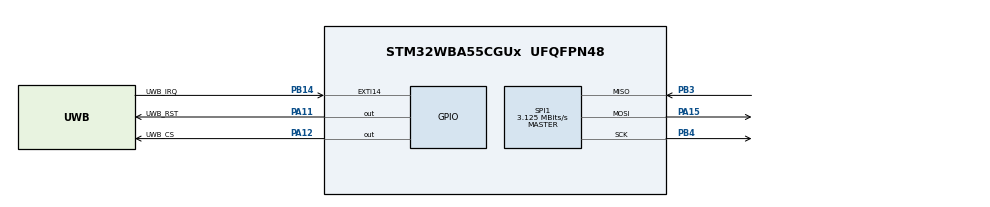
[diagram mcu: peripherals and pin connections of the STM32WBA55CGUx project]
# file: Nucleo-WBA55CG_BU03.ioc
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CORTEX_M33_NS.userName=CORTEX_M33
Mcu.Family=STM32WBA
Mcu.Name=STM32WBA55CGUx
Mcu.Package=UFQFPN48
NUCLEO-WBA55CG.BUTTON=1
NUCLEO-WBA55CG.BUTTON2=1
NUCLEO-WBA55CG.BUTTON3=1
NUCLEO-WBA55CG.LD1=true
NUCLEO-WBA55CG.LD2=true
NUCLEO-WBA55CG.LD3=true
NUCLEO-WBA55CG.VCP=true
NVIC.EXTI13_IRQn=true\:0\:0\:false\:false\:true\:false\:true\:true
NVIC.EXTI14_IRQn=true\:0\:0\:false\:false\:true\:true\:true\:true
NVIC.EXTI6_IRQn=true\:0\:0\:false\:false\:true\:false\:true\:true
NVIC.EXTI7_IRQn=true\:0\:0\:false\:false\:true\:false\:true\:true
NVIC.PriorityGroup=NVIC_PRIORITYGROUP_4
OSC_IN.GPIO_Label=RCC_OSC_IN
OSC_IN.Mode=HSE-External-Oscillator
OSC_IN.Signal=RCC_OSC_IN
OSC_OUT.GPIO_Label=RCC_OSC_OUT
OSC_OUT.Mode=HSE-External-Oscillator
OSC_OUT.Signal=RCC_OSC_OUT
PA11.GPIO_Label=UWB_RST
PA11.PinState=GPIO_PIN_SET
PA11.Signal=GPIO_Output
PA12.GPIO_Label=UWB_CS
PA12.PinState=GPIO_PIN_SET
PA12.Signal=GPIO_Output
PA13\ (JTMS/SWDIO).GPIO_Label=DEBUG_JTMS-SWDIO
PA13\ (JTMS/SWDIO).Mode=Serial_Wire
PA13\ (JTMS/SWDIO).Signal=DEBUG_JTMS-SWDIO
PA14\ (JTCK/SWCLK).GPIO_Label=DEBUG_JTCK-SWCLK
PA14\ (JTCK/SWCLK).Mode=Serial_Wire
PA14\ (JTCK/SWCLK).Signal=DEBUG_JTCK-SWCLK
PA15\ (JTDI).Mode=Full_Duplex_Master
PA15\ (JTDI).Signal=SPI1_MOSI
PA8.Signal=USART1_RX
PB12.Signal=USART1_TX
PB14.GPIO_Label=UWB_IRQ
PB14.Signal=GPXTI14
PB3\ (JTDO/TRACESWO).Mode=Full_Duplex_Master
PB3\ (JTDO/TRACESWO).Signal=SPI1_MISO
PB4\ (NJTRST).Mode=Full_Duplex_Master
PB4\ (NJTRST).Signal=SPI1_SCK
PC14-OSC32_IN.GPIO_Label=RCC_OSC32_IN
PC14-OSC32_IN.Signal=RCC_OSC32_IN
PC15-OSC32_OUT.GPIO_Label=RCC_OSC32_OUT
PC15-OSC32_OUT.Signal=RCC_OSC32_OUT
ProjectManager.HeapSize=0x200
ProjectManager.StackSize=0x400
ProjectManager.TargetToolchain=STM32CubeIDE
RCC.ADCFreq_Value=100000000
RCC.AHB5CLKDivider=DIV4
RCC.AHBFreq_Value=100000000
RCC.APB1Freq_Value=100000000
RCC.APB1TimFreq_Value=100000000
RCC.APB2Freq_Value=100000000
RCC.APB2TimFreq_Value=100000000
RCC.CortexFreq_Value=12500000
RCC.HCLKFreq_Value=100000000
RCC.HSE_VALUE=32000000
RCC.HSI_VALUE=16000000
RCC.LSE_VALUE=32768
RCC.LSI1_VALUE=32000
RCC.LSI2_VALUE=32000
RCC.PLLFRACN=4096
RCC.PLLN=12
RCC.PWR_Regulator_Voltage_Scale=PWR_REGULATOR_VOLTAGE_SCALE1
RCC.RTCClockSelection=RCC_RTCCLKSOURCE_LSE
RCC.SYSCLKFreq_VALUE=100000000
RCC.SYSCLKSourceVirtual=RCC_SYSCLKSOURCE_PLLCLK
RCC.VCOOutputFreq_Value=200000000
SPI1.BaudRatePrescaler=SPI_BAUDRATEPRESCALER_32
SPI1.CalculateBaudRate=3.125 MBits/s
SPI1.DataSize=SPI_DATASIZE_8BIT
SPI1.Direction=SPI_DIRECTION_2LINES
SPI1.Mode=SPI_MODE_MASTER
SPI1.VirtualType=VM_MASTER
VP_CORTEX_M33_NS_VS_Hclk.Mode=Hclk_Mode
VP_MEMORYMAP_VS_MEMORYMAP.Mode=CurAppReg
VP_NUCLEO-WBA55CG_VS_BSP_COMMON.Mode=COMMON
VP_PWR_VS_SECSignals.Mode=Security/Privilege
board=NUCLEO-WBA55CG

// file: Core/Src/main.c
/* USER CODE BEGIN Header */
/**
  ******************************************************************************
  * @file           : main.c
  * @brief          : Main program body
  ******************************************************************************
  * @attention
  *
  * Copyright (c) 2026 STMicroelectronics.
  * All rights reserved.
  *
  * This software is licensed under terms that can be found in the LICENSE file
  * in the root directory of this software component.
  * If no LICENSE file comes with this software, it is provided AS-IS.
  *
  ******************************************************************************
  */
/* USER CODE END Header */
#include "main.h"
#include "spi.h"
#include "gpio.h"

COM_InitTypeDef BspCOMInit;

void SystemClock_Config(void);

/* USER CODE BEGIN 0 */
#include <stdio.h>
#include <string.h>
#include "port.h"
#include "deca_device_api.h"
#include "dw3000_deca_regs.h"

#define TX_ANT_DLY 16385
#define RX_ANT_DLY 16385
#define ALL_MSG_SN_IDX 2
#define ALL_MSG_COMMON_LEN 10
#define RESP_MSG_POLL_RX_TS_IDX 10
#define RESP_MSG_RESP_TX_TS_IDX 14
#define POLL_RX_TO_RESP_TX_DLY_UUS 900 // Tag responds 900us after poll
#define UUS_TO_DWT_TIME 65536 // 1 uus = 65536 DWT time units

static dwt_config_t config = {
    5,               /* Channel number. */
    DWT_PLEN_128,    /* Preamble length. Used in TX only. */
    DWT_PAC8,        /* Preamble acquisition chunk size. Used in RX only. */
    9,               /* TX preamble code. Used in TX only. */
    9,               /* RX preamble code. Used in RX only. */
    1,               /* 0 to use standard 8 symbol SFD, 1 to use non-standard 8 symbol, 2 for non-standard 16 symbol SFD and 3 for 4z 8 symbol SDF type */
    DWT_BR_6M8,      /* Data rate. */
    DWT_PHRMODE_STD, /* PHY header mode. */
    DWT_PHRRATE_STD, /* PHY header rate. */
    (129 + 8 - 8),   /* SFD timeout (preamble length + 1 + SFD length - PAC size). Used in RX only. */
    DWT_STS_MODE_OFF,
    DWT_STS_LEN_64,  /* STS length, see allowed values in Enum dwt_sts_lengths_e */
    DWT_PDOA_M0      /* PDOA mode off */
};
static dwt_txconfig_t txconfig_options = {
    0x34,           /* PG delay. */
    0xfdfdfdfd,      /* TX power. */
    0x0             /* PG count. */
};

static uint8_t rx_buffer[20];
static uint8_t tx_resp_msg[] = {0x41, 0x88, 0, 0xCA, 0xDE, 'V', 'E', 'W', '0', 0xE1, 0, 0, 0, 0, 0, 0, 0, 0, 0, 0};
static uint8_t frame_seq_nb = 0;
static uint64_t poll_rx_ts;
static uint64_t resp_tx_ts;

static uint64_t get_rx_timestamp_u64(void)
{
    uint8_t ts_tab[5];
    uint64_t ts = 0;
    int i;
    dwt_readrxtimestamp(ts_tab, 0);
    for (i = 4; i >= 0; i--) {
        ts <<= 8;
        ts |= ts_tab[i];
    }
    return ts;
}

static void resp_msg_set_ts(uint8_t *ts_field, const uint64_t ts)
{
    int i;
    for (i = 0; i < 4; i++) {
        ts_field[i] = (uint8_t)(ts >> (i * 8));
    }
}
/* USER CODE END 0 */

int main(void)
{

  /* MCU Configuration--------------------------------------------------------*/

  /* Reset of all peripherals, Initializes the Flash interface and the Systick. */
  HAL_Init();

  /* Configure the system clock */
  SystemClock_Config();

  /* Initialize all configured peripherals */
  MX_GPIO_Init();
  MX_SPI1_Init();
  /* USER CODE BEGIN 2 */

  /* Initialize COM1 port */
  BspCOMInit.BaudRate   = 115200;
  BspCOMInit.WordLength = COM_WORDLENGTH_8B;
  BspCOMInit.StopBits   = COM_STOPBITS_1;
  BspCOMInit.Parity     = COM_PARITY_NONE;
  BspCOMInit.HwFlowCtl  = COM_HWCONTROL_NONE;
  if (BSP_COM_Init(COM1, &BspCOMInit) != BSP_ERROR_NONE)
  {
    Error_Handler();
  }

  printf("\r\n==================================\r\n");
  printf("STM32 Baremetal UWB TAG Started\r\n");
  printf("==================================\r\n");

  extern SPI_HandleTypeDef hspi1;
  extern SPI_HandleTypeDef *hcurrent_active_spi;
  extern uint16_t          pin_io_active_spi;

  hcurrent_active_spi = &hspi1;
  pin_io_active_spi = UWB_CS_Pin;

  reset_DWIC();      // Toggle RST pin

  // Simple Device ID check to verify SPI
  uint8_t tx_cmd[1] = {0x00};
  uint8_t rx_buf[4] = {0, 0, 0, 0};
  HAL_GPIO_WritePin(UWB_CS_GPIO_Port, UWB_CS_Pin, GPIO_PIN_RESET);
  HAL_SPI_Transmit(&hspi1, tx_cmd, 1, HAL_MAX_DELAY);
  HAL_SPI_Receive(&hspi1, rx_buf, 4, HAL_MAX_DELAY);
  HAL_GPIO_WritePin(UWB_CS_GPIO_Port, UWB_CS_Pin, GPIO_PIN_SET);
  uint32_t dev_id = (rx_buf[3] << 24) | (rx_buf[2] << 16) | (rx_buf[1] << 8) | rx_buf[0];
  printf("BU03 Device ID test: 0x%08lX\r\n", dev_id);

  extern const struct dwt_probe_s dw3000_probe_interf;
  if (dwt_probe((struct dwt_probe_s *)&dw3000_probe_interf) != DWT_SUCCESS) {
      printf("dwt_probe failed!\r\n");
      while (1) {};
  }

  while (!dwt_checkidlerc()) {
      printf("IDLE FAILED, retrying...\r\n");
      HAL_Delay(10);
  }

  if (dwt_initialise(DWT_DW_INIT) == DWT_ERROR) {
      printf("INIT FAILED\r\n");
      while (1);
  }

  dwt_setleds(DWT_LEDS_ENABLE | DWT_LEDS_INIT_BLINK);

  if (dwt_configure(&config)) {
      printf("CONFIG FAILED\r\n");
      while (1);
  }

  dwt_configuretxrf(&txconfig_options);
  dwt_setrxantennadelay(RX_ANT_DLY);
  dwt_settxantennadelay(TX_ANT_DLY);
  dwt_setlnapamode(DWT_LNA_ENABLE);

  printf("Tag (STM32) Ready! Listening for polls...\r\n");

  // Enable RX for the first time
  dwt_rxenable(DWT_START_RX_IMMEDIATE);

  /* USER CODE END 2 */

  /* Infinite loop */
  /* USER CODE BEGIN WHILE */
  while (1)
  {
    uint32_t status_reg;
    while (!((status_reg = dwt_read_reg(SYS_STATUS_ID)) &
             (SYS_STATUS_RXFCG_BIT_MASK | SYS_STATUS_ALL_RX_TO | SYS_STATUS_ALL_RX_ERR))) {
                 // Wait for packet
             }

    if (status_reg & SYS_STATUS_RXFCG_BIT_MASK) {
        dwt_write_reg(SYS_STATUS_ID, SYS_STATUS_RXFCG_BIT_MASK); // Clear flag

        uint32_t frame_len = dwt_read_reg(RX_FINFO_ID) & RX_FINFO_RXFLEN_BIT_MASK;
        if (frame_len <= sizeof(rx_buffer)) {
            dwt_readrxdata(rx_buffer, frame_len, 0);

            // Check if it's a Poll message (0xE0)
            if (rx_buffer[9] == 0xE0) {
                uint32_t resp_tx_time;

                poll_rx_ts = get_rx_timestamp_u64();

                resp_tx_time = (poll_rx_ts + ((uint64_t)POLL_RX_TO_RESP_TX_DLY_UUS * UUS_TO_DWT_TIME)) >> 8;
                dwt_setdelayedtrxtime(resp_tx_time);

                resp_tx_ts = (((uint64_t)(resp_tx_time & 0xFFFFFFFEUL)) << 8) + TX_ANT_DLY;

                resp_msg_set_ts(&tx_resp_msg[RESP_MSG_POLL_RX_TS_IDX], poll_rx_ts);
                resp_msg_set_ts(&tx_resp_msg[RESP_MSG_RESP_TX_TS_IDX], resp_tx_ts);

                // Echo back anchor ID byte ('1','2','3') and sequence number
                tx_resp_msg[8] = rx_buffer[8];
                tx_resp_msg[ALL_MSG_SN_IDX] = frame_seq_nb;

                dwt_writetxdata(sizeof(tx_resp_msg), tx_resp_msg, 0);
                dwt_writetxfctrl(sizeof(tx_resp_msg), 0, 1);

                if (dwt_starttx(DWT_START_TX_DELAYED) == DWT_SUCCESS) {
                    while (!(dwt_read_reg(SYS_STATUS_ID) & SYS_STATUS_TXFRS_BIT_MASK));
                    dwt_write_reg(SYS_STATUS_ID, SYS_STATUS_TXFRS_BIT_MASK);
                    frame_seq_nb++;

                    printf("[TAG] Responded to anchor: %c\r\n", (char)tx_resp_msg[8]);
                } else {
                    dwt_write_reg(SYS_STATUS_ID, SYS_STATUS_TXFRS_BIT_MASK);
                    printf("[TAG] Delayed TX missed — re-enabling RX\r\n");
                }
            }
        }
    } else {
        dwt_write_reg(SYS_STATUS_ID, SYS_STATUS_ALL_RX_TO | SYS_STATUS_ALL_RX_ERR);
    }

    // Always re-enable RX to listen for the next poll
    dwt_rxenable(DWT_START_RX_IMMEDIATE);

    /* USER CODE END WHILE */

  }
}

void SystemClock_Config(void)
{
  RCC_OscInitTypeDef RCC_OscInitStruct = {0};
  RCC_ClkInitTypeDef RCC_ClkInitStruct = {0};

  /** Supply configuration update enable
  */
  HAL_PWREx_ConfigSupply(PWR_LDO_SUPPLY);

  /** Configure the main internal regulator output voltage
  */
  if (HAL_PWREx_ControlVoltageScaling(PWR_REGULATOR_VOLTAGE_SCALE1) != HAL_OK)
  {
    Error_Handler();
  }

  /** Initializes the CPU, AHB and APB busses clocks
  */
  RCC_OscInitStruct.OscillatorType = RCC_OSCILLATORTYPE_HSI;
  RCC_OscInitStruct.HSIState = RCC_HSI_ON;
  RCC_OscInitStruct.HSICalibrationValue = RCC_HSICALIBRATION_DEFAULT;
  RCC_OscInitStruct.PLL1.PLLState = RCC_PLL_ON;
  RCC_OscInitStruct.PLL1.PLLSource = RCC_PLLSOURCE_HSI;
  RCC_OscInitStruct.PLL1.PLLM = 1;
  RCC_OscInitStruct.PLL1.PLLN = 12;
  RCC_OscInitStruct.PLL1.PLLP = 2;
  RCC_OscInitStruct.PLL1.PLLQ = 2;
  RCC_OscInitStruct.PLL1.PLLR = 2;
  RCC_OscInitStruct.PLL1.PLLFractional = 4096;
  if (HAL_RCC_OscConfig(&RCC_OscInitStruct) != HAL_OK)
  {
    Error_Handler();
  }

  /** Initializes the CPU, AHB and APB busses clocks
  */
  RCC_ClkInitStruct.ClockType = RCC_CLOCKTYPE_HCLK|RCC_CLOCKTYPE_SYSCLK
                              |RCC_CLOCKTYPE_PCLK1|RCC_CLOCKTYPE_PCLK2
                              |RCC_CLOCKTYPE_PCLK7|RCC_CLOCKTYPE_HCLK5;
  RCC_ClkInitStruct.SYSCLKSource = RCC_SYSCLKSOURCE_PLLCLK;
  RCC_ClkInitStruct.AHBCLKDivider = RCC_SYSCLK_DIV1;
  RCC_ClkInitStruct.APB1CLKDivider = RCC_HCLK_DIV1;
  RCC_ClkInitStruct.APB2CLKDivider = RCC_HCLK_DIV1;
  RCC_ClkInitStruct.APB7CLKDivider = RCC_HCLK_DIV1;
  RCC_ClkInitStruct.AHB5_PLL1_CLKDivider = RCC_SYSCLK_PLL1_DIV4;
  RCC_ClkInitStruct.AHB5_HSEHSI_CLKDivider = RCC_SYSCLK_HSEHSI_DIV1;

  if (HAL_RCC_ClockConfig(&RCC_ClkInitStruct, FLASH_LATENCY_3) != HAL_OK)
  {
    Error_Handler();
  }
}

void Error_Handler(void)
{
  __disable_irq();
  while (1)
  {
  }
}
